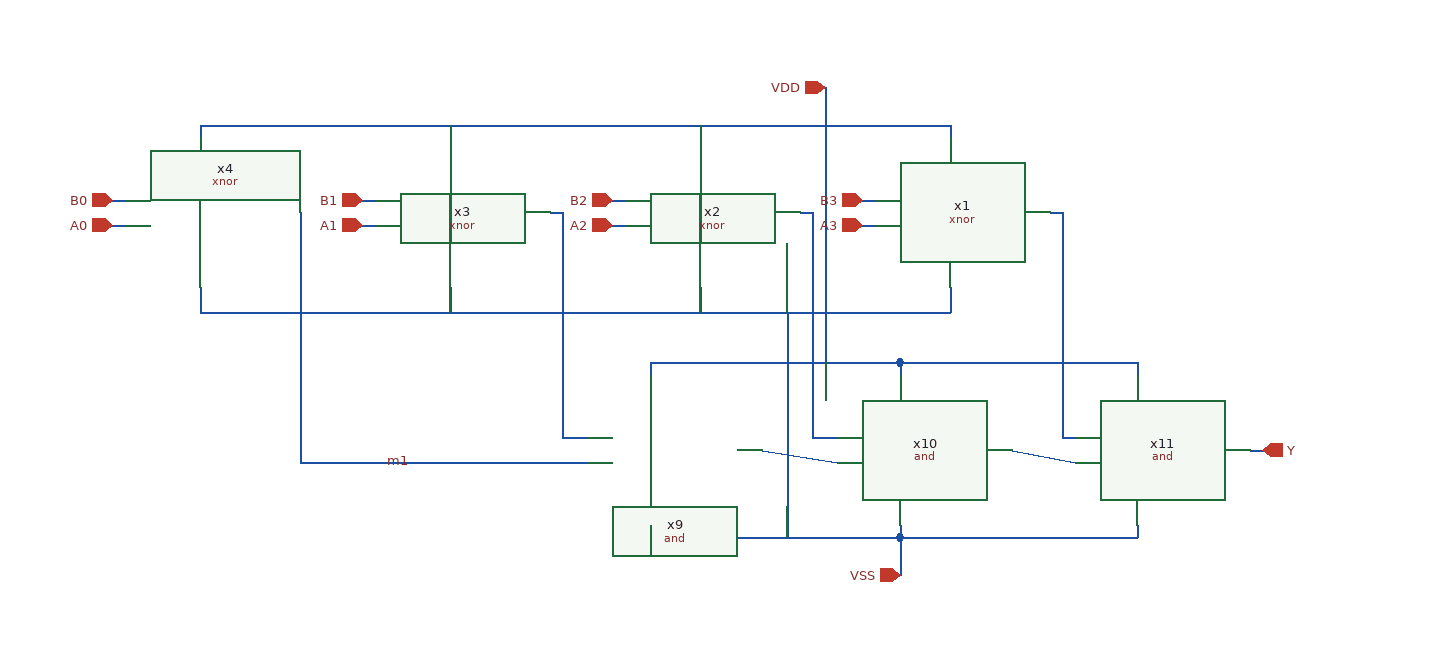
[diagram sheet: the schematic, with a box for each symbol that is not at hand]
v {xschem version=3.4.6RC file_version=1.2
}
G {}
K {}
V {}
S {}
E {}
N 360 220 560 220 {lab=VDD}
N 560 220 760 220 {lab=VDD}
N 170 370 360 370 {lab=VSS}
N 360 370 560 370 {lab=VSS}
N 560 370 760 370 {lab=VSS}
N 250 300 250 490 {lab=m1}
N 450 290 460 290 {lab=#net1}
N 460 290 460 470 {lab=#net1}
N 460 470 480 470 {lab=#net1}
N 650 290 660 290 {lab=#net2}
N 660 290 660 470 {lab=#net2}
N 660 470 680 470 {lab=#net2}
N 620 480 680 490 {lab=#net3}
N 850 290 860 290 {lab=#net4}
N 860 290 860 470 {lab=#net4}
N 860 470 870 470 {lab=#net4}
N 820 480 870 490 {lab=#net5}
N 920 410 920 420 {lab=VDD}
N 730 410 920 410 {lab=VDD}
N 730 410 730 420 {lab=VDD}
N 530 410 730 410 {lab=VDD}
N 530 410 530 420 {lab=VDD}
N 530 540 530 550 {lab=VSS}
N 530 550 730 550 {lab=VSS}
N 730 540 730 550 {lab=VSS}
N 730 550 920 550 {lab=VSS}
N 920 540 920 550 {lab=VSS}
N 670 220 670 410 {lab=VDD}
N 640 370 640 550 {lab=VSS}
N 250 290 250 300 {lab=m1}
N 250 490 480 490 {lab=m1}
N 1010 480 1020 480 {lab=Y}
N 670 190 670 220 {lab=VDD}
N 730 550 730 580 {lab=VSS}
N 370 350 370 370 {lab=VSS}
N 570 350 570 370 {lab=VSS}
N 770 350 770 370 {lab=VSS}
N 760 370 770 370 {lab=VSS}
N 760 220 770 220 {lab=VDD}
N 770 220 770 230 {lab=VDD}
N 570 220 570 230 {lab=VDD}
N 370 220 370 230 {lab=VDD}
N 170 350 170 370 {lab=VSS}
N 170 220 170 230 {lab=VDD}
N 170 220 360 220 {lab=VDD}
N 100 280 110 280 {lab=B0}
N 100 300 110 300 {lab=A0}
N 300 300 310 300 {lab=A1}
N 300 280 310 280 {lab=A1}
N 500 280 510 280 {lab=B2}
N 500 300 510 300 {lab=A2}
N 700 300 710 300 {lab=A3}
N 700 280 710 280 {lab=B3}
C {and.sym} 540 480 0 0 {name=x9}
C {and.sym} 740 480 0 0 {name=x10}
C {and.sym} 930 480 0 0 {name=x11}
C {lab_wire.sym} 340 490 0 0 {name=m1 sig_type=std_logic lab=m1}
C {ipin.sym} 670 190 0 0 {name=p3 lab=VDD}
C {opin.sym} 1020 480 0 0 {name=p1 lab=Y}
C {ipin.sym} 730 580 0 0 {name=p2 lab=VSS}
C {ipin.sym} 100 280 0 0 {name=p4 lab=B0}
C {ipin.sym} 300 280 0 0 {name=p5 lab=B1}
C {ipin.sym} 500 280 0 0 {name=p6 lab=B2}
C {ipin.sym} 700 280 0 0 {name=p7 lab=B3}
C {ipin.sym} 100 300 0 0 {name=p8 lab=A0}
C {ipin.sym} 300 300 0 0 {name=p9 lab=A1}
C {ipin.sym} 500 300 0 0 {name=p10 lab=A2}
C {ipin.sym} 700 300 0 0 {name=p11 lab=A3}
C {xnor.sym} 770 290 0 0 {name=x1}
C {xnor.sym} 570 290 0 0 {name=x2}
C {xnor.sym} 370 290 0 0 {name=x3}
C {xnor.sym} 170 290 0 0 {name=x4}
